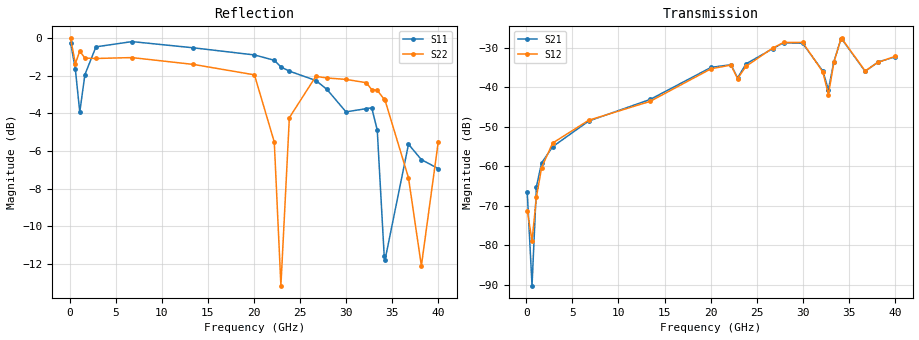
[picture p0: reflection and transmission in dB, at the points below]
!  2-Port S-parameters saved by WinCal
! VAR MeasName=S-Parameters (CALIBRATED_DATA) read from VNA (E8364A)
! VAR MeasDate=5/8/2013 4:19:51 PM
! VAR NAME=131610 2
! VAR FILENAME=131610 2.S2P
! VAR DATE=5/8/2013 4:19:51 PM
! VAR PHYS_PORTS=1,2
# Hz S MA R 50
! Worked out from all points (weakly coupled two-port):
!   1001 points, 100 MHz to 40 GHz, reference 50 ohm
!   highest |S21| = -27.79 dB at 34.21 GHz (marker M1); lowest = -90.2 dB at 618.7 MHz (marker M2)
!   lowest |S11| = -11.8 dB at 34.21 GHz (marker M3), VSWR 1.69, Z = 29.8 - j3.85 ohm
!   |S11| at or under -10 dB: 33.99 GHz to 34.57 GHz (579.1 MHz wide, 1.69 % of centre); 34.57488 GHz to 34.63085 GHz (55.97 MHz wide, 0.162 % of centre)
!   |S22| runs from -13.2 to 0.7 dB; largest |S21 - S12| = 0.0037
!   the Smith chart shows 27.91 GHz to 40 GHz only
!   S11 on the Smith chart (normalised r, x): 27.91 GHz: 0.53, +1.48; 29.99 GHz: 3.93, -1.45; 32.18 GHz: 0.34, -0.73; 34.13 GHz: 0.59, -0.06; 36.77 GHz: 0.34, +0.26; 40 GHz: 2.46, +0.61
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1e8  0.9711 -10.6  0.00047 128.6  0.0002742 91.9  0.9971 -11.7
6.187e8  0.8254 -63.8  3.076e-05 78.9  0.0001137 143.5  0.8546 -59.2
1.0975e9  0.6355 -175.8  0.0005512 -175.9  0.0004069 -152.8  0.9223 -100.1
1.6561e9  0.7994 71.7  0.001099 134.4  0.0009588 136.7  0.8839 -128.3
2.8531e9  0.9467 7.9  0.001759 98.9  0.001959 93.4  0.8818 -155.8
6.7633e9  0.9776 -57.1  0.00372 57.1  0.003805 56.2  0.8867 156.0
1.34266e10  0.9412 -122.7  0.006971 24.3  0.006596 26.3  0.8505 100.8
2.005e10  0.9011 -176.9  0.01775 -29.9  0.01706 -32.5  0.7979 29.0
2.22046e10  0.8722 160.8  0.01919 -70.1  0.01898 -69.9  0.5294 -12.6
2.29228e10  0.8374 152.1  0.01307 -74.5  0.0128 -72.1  0.2201 13.5
2.38405e10  0.8162 144.9  0.01968 -55.8  0.01834 -58.3  0.6143 32.5
2.67133e10  0.7708 95.6  0.03048 -101.9  0.03105 -97.9  0.7907 -19.6
2.79103e10  0.7305 63.7  0.03649 -126.1  0.03668 -123.3  0.7828 -34.2
2.99851e10  0.6364 -9.9  0.03577 -169.7  0.03676 -169.7  0.776 -58.7
3.21796e10  0.649 -103.3  0.0159 145.6  0.0155 147.2  0.7606 -84.1
3.27781e10  0.6525 -130.0  0.009259 -173.4  0.008025 -170.5  0.7292 -92.4
3.33766e10  0.5695 -160.1  0.02107 -140.6  0.02057 -139.4  0.7261 -100.8
3.41347e10  0.2632 -169.9  0.04024 178.1  0.04076 -179.8  0.6869 -111.6
3.42145e10  0.2571 -166.4  0.04077 173.5  0.04134 175.0  0.6843 -113.0
3.67681e10  0.5223 148.2  0.01582 132.5  0.01602 129.2  0.4254 176.6
3.81646e10  0.4753 95.0  0.02075 142.3  0.02059 140.8  0.2484 69.5
4e10  0.4501 12.7  0.02411 132.6  0.02443 134.5  0.5305 -31.8
